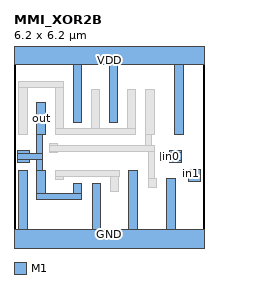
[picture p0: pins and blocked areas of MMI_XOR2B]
MACRO MMI_XOR2B
	CLASS CORE ;
	FOREIGN MMI_XOR2B 0 0 ;
	SIZE 6.2 BY 6.2 ;
	SYMMETRY X Y ;
	SITE CORE1 ;
	PIN out
		DIRECTION output ;
		USE SIGNAL ;
		PORT
			LAYER M1 ;
			RECT 0.75 3.505 1.03 4.565 ;
			LAYER M1 ;
			RECT 0.12 2.885 0.5 2.98 ;
			LAYER M1 ;
			RECT 0.75 2.885 0.94 3.505 ;
			LAYER M1 ;
			RECT 0.12 2.695 0.94 2.885 ;
			LAYER M1 ;
			RECT 0.12 2.6 0.5 2.695 ;
			LAYER M1 ;
			RECT 0.75 2.335 0.94 2.695 ;
			LAYER M1 ;
			RECT 0.75 1.575 1.03 2.335 ;
			LAYER M1 ;
			RECT 1.93 1.575 2.21 1.915 ;
			LAYER M1 ;
			RECT 0.75 1.385 2.21 1.575 ;
		END
		AntennaDiffArea 1.32055 ;
	END out
	PIN in1
		DIRECTION input ;
		USE SIGNAL ;
		PORT
			LAYER M1 ;
			RECT 5.49 2.36 5.77 2.375 ;
			LAYER M1 ;
			RECT 5.49 2.095 6.085 2.36 ;
			LAYER M1 ;
			RECT 5.705 1.98 6.085 2.095 ;
		END
		AntennaGateArea 0.98175 ;
	END in1
	PIN GND
		DIRECTION inout ;
		USE GROUND ;
		PORT
			LAYER M1 ;
			RECT 0.16 0.42 0.44 2.335 ;
			LAYER M1 ;
			RECT 2.555 0.42 2.835 1.915 ;
			LAYER M1 ;
			RECT 3.735 0.42 4.015 2.335 ;
			LAYER M1 ;
			RECT 4.975 0.42 5.255 2.085 ;
			LAYER M1 ;
			RECT 0 -0.42 6.2 0.42 ;
		END
	END GND
	PIN VDD
		DIRECTION inout ;
		USE POWER ;
		PORT
			LAYER M1 ;
			RECT 0 5.78 6.2 6.62 ;
			LAYER M1 ;
			RECT 1.93 3.915 2.21 5.78 ;
			LAYER M1 ;
			RECT 3.11 3.915 3.39 5.78 ;
			LAYER M1 ;
			RECT 5.25 3.505 5.53 5.78 ;
		END
	END VDD
	PIN in0
		DIRECTION input ;
		USE SIGNAL ;
		PORT
			LAYER M1 ;
			RECT 5.08 2.935 5.46 2.98 ;
			LAYER M1 ;
			RECT 5.06 2.93 5.46 2.935 ;
			LAYER M1 ;
			RECT 4.78 2.65 5.46 2.93 ;
			LAYER M1 ;
			RECT 5.08 2.6 5.46 2.65 ;
		END
		AntennaGateArea 0.98175 ;
	END in0
	OBS
		LAYER M1 ;
		RECT 0.16 5.035 1.62 5.23 ;
		LAYER M1 ;
		RECT 0.16 3.505 0.44 5.035 ;
		LAYER M1 ;
		RECT 1.34 3.695 1.62 5.035 ;
		LAYER M1 ;
		RECT 2.52 3.695 2.8 4.975 ;
		LAYER M1 ;
		RECT 3.7 3.695 3.98 4.975 ;
		LAYER M1 ;
		RECT 1.34 3.505 3.98 3.695 ;
		LAYER M1 ;
		RECT 4.29 3.505 4.57 4.975 ;
		LAYER M1 ;
		RECT 1.145 3.16 1.425 3.205 ;
		LAYER M1 ;
		RECT 4.29 3.16 4.48 3.505 ;
		LAYER M1 ;
		RECT 1.145 2.965 4.575 3.16 ;
		LAYER M1 ;
		RECT 1.145 2.925 1.425 2.965 ;
		LAYER M1 ;
		RECT 1.36 2.335 3.435 2.34 ;
		LAYER M1 ;
		RECT 1.34 2.145 3.435 2.335 ;
		LAYER M1 ;
		RECT 1.34 2.055 1.62 2.145 ;
		LAYER M1 ;
		RECT 3.145 1.635 3.425 2.145 ;
		LAYER M1 ;
		RECT 4.385 2.085 4.575 2.965 ;
		LAYER M1 ;
		RECT 4.385 1.77 4.665 2.085 ;
	END
END MMI_XOR2B
